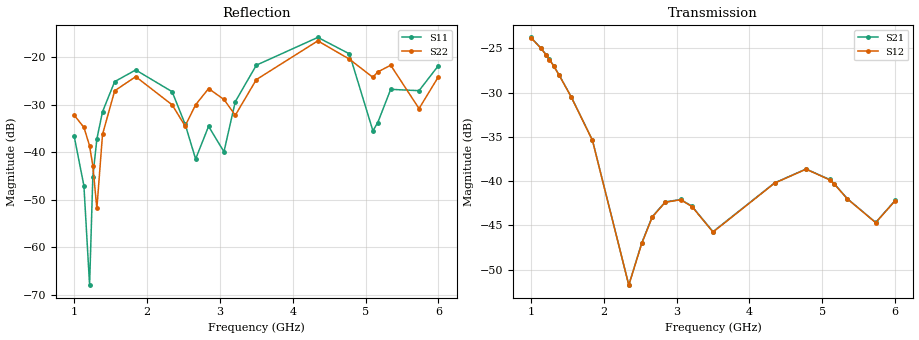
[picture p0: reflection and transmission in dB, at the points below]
!Agilent Technologies,E8364B,MY43040528,A.07.50.67
!Agilent E8364B: A.07.50.67
!Date: Sunday, March 01, 2026 22:59:08
!Correction: S11(Full 2 Port(1,2))
!S21(Full 2 Port(1,2))
!S12(Full 2 Port(1,2))
!S22(Full 2 Port(1,2))
!S2P File: Measurements: S11, S21, S12, S22:
# Hz S  dB  R 50
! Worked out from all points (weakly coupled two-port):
!   451 points, 1 GHz to 6 GHz, reference 50 ohm
!   highest |S21| = -23.76 dB at 1 GHz (marker M1); lowest = -51.8 dB at 2.344 GHz (marker M2)
!   lowest |S11| = -67.9 dB at 1.211 GHz (marker M3), VSWR 1.00, Z = 50 - j0.0116 ohm
!   |S11| at or under -10 dB: start of sweep to end of sweep
!   |S22| runs from -51.8 to -16.5 dB; largest |S21 - S12| = 0.00025
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1e9  -36.61 16.3  -23.76 154.9  -23.80 154.9  -32.15 -13.3
1.133333e9  -47.02 17.5  -24.93 78.7  -24.95 78.8  -34.72 -21.6
1.211111e9  -67.93 -163.2  -25.73 34.5  -25.77 34.5  -38.59 -33.3
1.255556e9  -45.14 -160.2  -26.25 9.4  -26.28 9.4  -42.79 -55.3
1.311111e9  -37.15 -166.1  -26.95 -21.9  -26.98 -21.8  -51.79 -154.4
1.388889e9  -31.42 176.4  -28.02 -65.1  -28.05 -65.1  -36.18 117.5
1.555556e9  -25.08 136.5  -30.50 -155.4  -30.53 -155.4  -27.01 64.5
1.844444e9  -22.63 76.7  -35.36 51.0  -35.39 51.1  -24.04 -9.0
2.344444e9  -27.21 1.9  -51.75 -148.8  -51.76 -149.1  -29.97 -90.3
2.522222e9  -34.03 -21.2  -46.99 171.8  -47.05 171.8  -34.43 -75.5
2.666667e9  -41.38 41.2  -44.01 104.0  -44.06 104.0  -29.96 -62.8
2.844444e9  -34.49 49.4  -42.36 12.8  -42.40 12.7  -26.55 -95.6
3.055556e9  -39.86 80.3  -42.08 -97.9  -42.11 -97.8  -28.84 -135.1
3.211111e9  -29.30 109.4  -42.84 -178.3  -42.88 -178.3  -32.17 -122.9
3.5e9  -21.62 63.6  -45.72 46.4  -45.77 46.5  -24.66 -131.6
4.344444e9  -15.77 -41.6  -40.21 23.7  -40.24 23.7  -16.50 111.5
4.777778e9  -19.24 -115.7  -38.63 142.8  -38.66 142.8  -20.36 34.5
5.1e9  -35.43 -120.6  -39.82 -46.9  -39.86 -46.9  -24.18 33.9
5.166667e9  -33.72 -72.9  -40.32 -87.1  -40.36 -87.2  -23.05 29.8
5.344444e9  -26.71 -76.4  -41.99 162.0  -42.02 162.0  -21.63 0.4
5.733333e9  -26.99 -72.2  -44.68 -112.4  -44.70 -112.4  -30.76 -26.7
6e9  -21.70 -82.1  -42.19 59.9  -42.23 60.0  -24.05 -21.2
